VERSION 5.7 ;
BUSBITCHARS "[]" ;
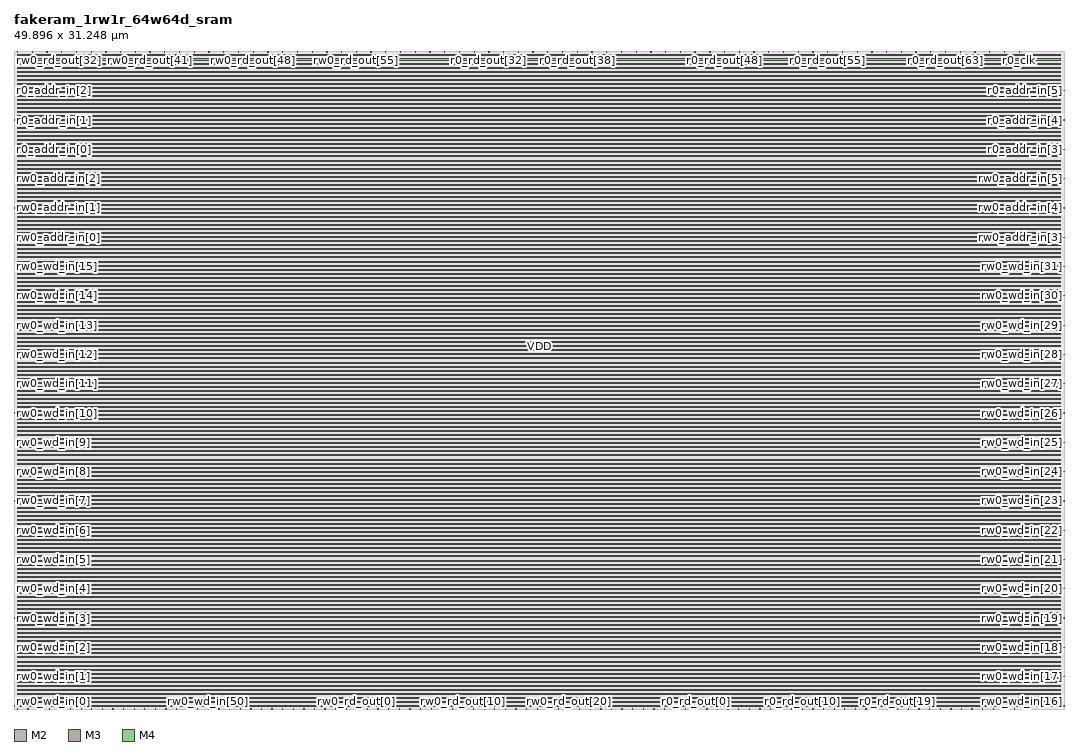
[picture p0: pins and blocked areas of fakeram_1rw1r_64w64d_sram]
MACRO fakeram_1rw1r_64w64d_sram
  FOREIGN fakeram_1rw1r_64w64d_sram 0 0 ;
  SYMMETRY X Y R90 ;
  SIZE 49.896 BY 31.248 ;
  CLASS BLOCK ;
  PIN rw0_wd_in[0]
    DIRECTION INPUT ;
    USE SIGNAL ;
    SHAPE ABUTMENT ;
    PORT
      LAYER M2 ;
      RECT 0.000 0.138 0.036 0.150 ;
    END
  END rw0_wd_in[0]
  PIN rw0_wd_in[1]
    DIRECTION INPUT ;
    USE SIGNAL ;
    SHAPE ABUTMENT ;
    PORT
      LAYER M2 ;
      RECT 0.000 1.530 0.036 1.542 ;
    END
  END rw0_wd_in[1]
  PIN rw0_wd_in[2]
    DIRECTION INPUT ;
    USE SIGNAL ;
    SHAPE ABUTMENT ;
    PORT
      LAYER M2 ;
      RECT 0.000 2.922 0.036 2.934 ;
    END
  END rw0_wd_in[2]
  PIN rw0_wd_in[3]
    DIRECTION INPUT ;
    USE SIGNAL ;
    SHAPE ABUTMENT ;
    PORT
      LAYER M2 ;
      RECT 0.000 4.314 0.036 4.326 ;
    END
  END rw0_wd_in[3]
  PIN rw0_wd_in[4]
    DIRECTION INPUT ;
    USE SIGNAL ;
    SHAPE ABUTMENT ;
    PORT
      LAYER M2 ;
      RECT 0.000 5.706 0.036 5.718 ;
    END
  END rw0_wd_in[4]
  PIN rw0_wd_in[5]
    DIRECTION INPUT ;
    USE SIGNAL ;
    SHAPE ABUTMENT ;
    PORT
      LAYER M2 ;
      RECT 0.000 7.098 0.036 7.110 ;
    END
  END rw0_wd_in[5]
  PIN rw0_wd_in[6]
    DIRECTION INPUT ;
    USE SIGNAL ;
    SHAPE ABUTMENT ;
    PORT
      LAYER M2 ;
      RECT 0.000 8.490 0.036 8.502 ;
    END
  END rw0_wd_in[6]
  PIN rw0_wd_in[7]
    DIRECTION INPUT ;
    USE SIGNAL ;
    SHAPE ABUTMENT ;
    PORT
      LAYER M2 ;
      RECT 0.000 9.882 0.036 9.894 ;
    END
  END rw0_wd_in[7]
  PIN rw0_wd_in[8]
    DIRECTION INPUT ;
    USE SIGNAL ;
    SHAPE ABUTMENT ;
    PORT
      LAYER M2 ;
      RECT 0.000 11.274 0.036 11.286 ;
    END
  END rw0_wd_in[8]
  PIN rw0_wd_in[9]
    DIRECTION INPUT ;
    USE SIGNAL ;
    SHAPE ABUTMENT ;
    PORT
      LAYER M2 ;
      RECT 0.000 12.666 0.036 12.678 ;
    END
  END rw0_wd_in[9]
  PIN rw0_wd_in[10]
    DIRECTION INPUT ;
    USE SIGNAL ;
    SHAPE ABUTMENT ;
    PORT
      LAYER M2 ;
      RECT 0.000 14.058 0.036 14.070 ;
    END
  END rw0_wd_in[10]
  PIN rw0_wd_in[11]
    DIRECTION INPUT ;
    USE SIGNAL ;
    SHAPE ABUTMENT ;
    PORT
      LAYER M2 ;
      RECT 0.000 15.450 0.036 15.462 ;
    END
  END rw0_wd_in[11]
  PIN rw0_wd_in[12]
    DIRECTION INPUT ;
    USE SIGNAL ;
    SHAPE ABUTMENT ;
    PORT
      LAYER M2 ;
      RECT 0.000 16.842 0.036 16.854 ;
    END
  END rw0_wd_in[12]
  PIN rw0_wd_in[13]
    DIRECTION INPUT ;
    USE SIGNAL ;
    SHAPE ABUTMENT ;
    PORT
      LAYER M2 ;
      RECT 0.000 18.234 0.036 18.246 ;
    END
  END rw0_wd_in[13]
  PIN rw0_wd_in[14]
    DIRECTION INPUT ;
    USE SIGNAL ;
    SHAPE ABUTMENT ;
    PORT
      LAYER M2 ;
      RECT 0.000 19.626 0.036 19.638 ;
    END
  END rw0_wd_in[14]
  PIN rw0_wd_in[15]
    DIRECTION INPUT ;
    USE SIGNAL ;
    SHAPE ABUTMENT ;
    PORT
      LAYER M2 ;
      RECT 0.000 21.018 0.036 21.030 ;
    END
  END rw0_wd_in[15]
  PIN rw0_wd_in[16]
    DIRECTION INPUT ;
    USE SIGNAL ;
    SHAPE ABUTMENT ;
    PORT
      LAYER M2 ;
      RECT 49.860 0.138 49.896 0.150 ;
    END
  END rw0_wd_in[16]
  PIN rw0_wd_in[17]
    DIRECTION INPUT ;
    USE SIGNAL ;
    SHAPE ABUTMENT ;
    PORT
      LAYER M2 ;
      RECT 49.860 1.530 49.896 1.542 ;
    END
  END rw0_wd_in[17]
  PIN rw0_wd_in[18]
    DIRECTION INPUT ;
    USE SIGNAL ;
    SHAPE ABUTMENT ;
    PORT
      LAYER M2 ;
      RECT 49.860 2.922 49.896 2.934 ;
    END
  END rw0_wd_in[18]
  PIN rw0_wd_in[19]
    DIRECTION INPUT ;
    USE SIGNAL ;
    SHAPE ABUTMENT ;
    PORT
      LAYER M2 ;
      RECT 49.860 4.314 49.896 4.326 ;
    END
  END rw0_wd_in[19]
  PIN rw0_wd_in[20]
    DIRECTION INPUT ;
    USE SIGNAL ;
    SHAPE ABUTMENT ;
    PORT
      LAYER M2 ;
      RECT 49.860 5.706 49.896 5.718 ;
    END
  END rw0_wd_in[20]
  PIN rw0_wd_in[21]
    DIRECTION INPUT ;
    USE SIGNAL ;
    SHAPE ABUTMENT ;
    PORT
      LAYER M2 ;
      RECT 49.860 7.098 49.896 7.110 ;
    END
  END rw0_wd_in[21]
  PIN rw0_wd_in[22]
    DIRECTION INPUT ;
    USE SIGNAL ;
    SHAPE ABUTMENT ;
    PORT
      LAYER M2 ;
      RECT 49.860 8.490 49.896 8.502 ;
    END
  END rw0_wd_in[22]
  PIN rw0_wd_in[23]
    DIRECTION INPUT ;
    USE SIGNAL ;
    SHAPE ABUTMENT ;
    PORT
      LAYER M2 ;
      RECT 49.860 9.882 49.896 9.894 ;
    END
  END rw0_wd_in[23]
  PIN rw0_wd_in[24]
    DIRECTION INPUT ;
    USE SIGNAL ;
    SHAPE ABUTMENT ;
    PORT
      LAYER M2 ;
      RECT 49.860 11.274 49.896 11.286 ;
    END
  END rw0_wd_in[24]
  PIN rw0_wd_in[25]
    DIRECTION INPUT ;
    USE SIGNAL ;
    SHAPE ABUTMENT ;
    PORT
      LAYER M2 ;
      RECT 49.860 12.666 49.896 12.678 ;
    END
  END rw0_wd_in[25]
  PIN rw0_wd_in[26]
    DIRECTION INPUT ;
    USE SIGNAL ;
    SHAPE ABUTMENT ;
    PORT
      LAYER M2 ;
      RECT 49.860 14.058 49.896 14.070 ;
    END
  END rw0_wd_in[26]
  PIN rw0_wd_in[27]
    DIRECTION INPUT ;
    USE SIGNAL ;
    SHAPE ABUTMENT ;
    PORT
      LAYER M2 ;
      RECT 49.860 15.450 49.896 15.462 ;
    END
  END rw0_wd_in[27]
  PIN rw0_wd_in[28]
    DIRECTION INPUT ;
    USE SIGNAL ;
    SHAPE ABUTMENT ;
    PORT
      LAYER M2 ;
      RECT 49.860 16.842 49.896 16.854 ;
    END
  END rw0_wd_in[28]
  PIN rw0_wd_in[29]
    DIRECTION INPUT ;
    USE SIGNAL ;
    SHAPE ABUTMENT ;
    PORT
      LAYER M2 ;
      RECT 49.860 18.234 49.896 18.246 ;
    END
  END rw0_wd_in[29]
  PIN rw0_wd_in[30]
    DIRECTION INPUT ;
    USE SIGNAL ;
    SHAPE ABUTMENT ;
    PORT
      LAYER M2 ;
      RECT 49.860 19.626 49.896 19.638 ;
    END
  END rw0_wd_in[30]
  PIN rw0_wd_in[31]
    DIRECTION INPUT ;
    USE SIGNAL ;
    SHAPE ABUTMENT ;
    PORT
      LAYER M2 ;
      RECT 49.860 21.018 49.896 21.030 ;
    END
  END rw0_wd_in[31]
  PIN rw0_wd_in[32]
    DIRECTION INPUT ;
    USE SIGNAL ;
    SHAPE ABUTMENT ;
    PORT
      LAYER M3 ;
      RECT 0.161 0.000 0.175 0.042 ;
    END
  END rw0_wd_in[32]
  PIN rw0_wd_in[33]
    DIRECTION INPUT ;
    USE SIGNAL ;
    SHAPE ABUTMENT ;
    PORT
      LAYER M3 ;
      RECT 0.665 0.000 0.679 0.042 ;
    END
  END rw0_wd_in[33]
  PIN rw0_wd_in[34]
    DIRECTION INPUT ;
    USE SIGNAL ;
    SHAPE ABUTMENT ;
    PORT
      LAYER M3 ;
      RECT 1.169 0.000 1.183 0.042 ;
    END
  END rw0_wd_in[34]
  PIN rw0_wd_in[35]
    DIRECTION INPUT ;
    USE SIGNAL ;
    SHAPE ABUTMENT ;
    PORT
      LAYER M3 ;
      RECT 1.673 0.000 1.687 0.042 ;
    END
  END rw0_wd_in[35]
  PIN rw0_wd_in[36]
    DIRECTION INPUT ;
    USE SIGNAL ;
    SHAPE ABUTMENT ;
    PORT
      LAYER M3 ;
      RECT 2.177 0.000 2.191 0.042 ;
    END
  END rw0_wd_in[36]
  PIN rw0_wd_in[37]
    DIRECTION INPUT ;
    USE SIGNAL ;
    SHAPE ABUTMENT ;
    PORT
      LAYER M3 ;
      RECT 2.681 0.000 2.695 0.042 ;
    END
  END rw0_wd_in[37]
  PIN rw0_wd_in[38]
    DIRECTION INPUT ;
    USE SIGNAL ;
    SHAPE ABUTMENT ;
    PORT
      LAYER M3 ;
      RECT 3.185 0.000 3.199 0.042 ;
    END
  END rw0_wd_in[38]
  PIN rw0_wd_in[39]
    DIRECTION INPUT ;
    USE SIGNAL ;
    SHAPE ABUTMENT ;
    PORT
      LAYER M3 ;
      RECT 3.689 0.000 3.703 0.042 ;
    END
  END rw0_wd_in[39]
  PIN rw0_wd_in[40]
    DIRECTION INPUT ;
    USE SIGNAL ;
    SHAPE ABUTMENT ;
    PORT
      LAYER M3 ;
      RECT 4.193 0.000 4.207 0.042 ;
    END
  END rw0_wd_in[40]
  PIN rw0_wd_in[41]
    DIRECTION INPUT ;
    USE SIGNAL ;
    SHAPE ABUTMENT ;
    PORT
      LAYER M3 ;
      RECT 4.697 0.000 4.711 0.042 ;
    END
  END rw0_wd_in[41]
  PIN rw0_wd_in[42]
    DIRECTION INPUT ;
    USE SIGNAL ;
    SHAPE ABUTMENT ;
    PORT
      LAYER M3 ;
      RECT 5.201 0.000 5.215 0.042 ;
    END
  END rw0_wd_in[42]
  PIN rw0_wd_in[43]
    DIRECTION INPUT ;
    USE SIGNAL ;
    SHAPE ABUTMENT ;
    PORT
      LAYER M3 ;
      RECT 5.705 0.000 5.719 0.042 ;
    END
  END rw0_wd_in[43]
  PIN rw0_wd_in[44]
    DIRECTION INPUT ;
    USE SIGNAL ;
    SHAPE ABUTMENT ;
    PORT
      LAYER M3 ;
      RECT 6.209 0.000 6.223 0.042 ;
    END
  END rw0_wd_in[44]
  PIN rw0_wd_in[45]
    DIRECTION INPUT ;
    USE SIGNAL ;
    SHAPE ABUTMENT ;
    PORT
      LAYER M3 ;
      RECT 6.713 0.000 6.727 0.042 ;
    END
  END rw0_wd_in[45]
  PIN rw0_wd_in[46]
    DIRECTION INPUT ;
    USE SIGNAL ;
    SHAPE ABUTMENT ;
    PORT
      LAYER M3 ;
      RECT 7.217 0.000 7.231 0.042 ;
    END
  END rw0_wd_in[46]
  PIN rw0_wd_in[47]
    DIRECTION INPUT ;
    USE SIGNAL ;
    SHAPE ABUTMENT ;
    PORT
      LAYER M3 ;
      RECT 7.721 0.000 7.735 0.042 ;
    END
  END rw0_wd_in[47]
  PIN rw0_wd_in[48]
    DIRECTION INPUT ;
    USE SIGNAL ;
    SHAPE ABUTMENT ;
    PORT
      LAYER M3 ;
      RECT 8.225 0.000 8.239 0.042 ;
    END
  END rw0_wd_in[48]
  PIN rw0_wd_in[49]
    DIRECTION INPUT ;
    USE SIGNAL ;
    SHAPE ABUTMENT ;
    PORT
      LAYER M3 ;
      RECT 8.729 0.000 8.743 0.042 ;
    END
  END rw0_wd_in[49]
  PIN rw0_wd_in[50]
    DIRECTION INPUT ;
    USE SIGNAL ;
    SHAPE ABUTMENT ;
    PORT
      LAYER M3 ;
      RECT 9.233 0.000 9.247 0.042 ;
    END
  END rw0_wd_in[50]
  PIN rw0_wd_in[51]
    DIRECTION INPUT ;
    USE SIGNAL ;
    SHAPE ABUTMENT ;
    PORT
      LAYER M3 ;
      RECT 9.737 0.000 9.751 0.042 ;
    END
  END rw0_wd_in[51]
  PIN rw0_wd_in[52]
    DIRECTION INPUT ;
    USE SIGNAL ;
    SHAPE ABUTMENT ;
    PORT
      LAYER M3 ;
      RECT 10.241 0.000 10.255 0.042 ;
    END
  END rw0_wd_in[52]
  PIN rw0_wd_in[53]
    DIRECTION INPUT ;
    USE SIGNAL ;
    SHAPE ABUTMENT ;
    PORT
      LAYER M3 ;
      RECT 10.745 0.000 10.759 0.042 ;
    END
  END rw0_wd_in[53]
  PIN rw0_wd_in[54]
    DIRECTION INPUT ;
    USE SIGNAL ;
    SHAPE ABUTMENT ;
    PORT
      LAYER M3 ;
      RECT 11.249 0.000 11.263 0.042 ;
    END
  END rw0_wd_in[54]
  PIN rw0_wd_in[55]
    DIRECTION INPUT ;
    USE SIGNAL ;
    SHAPE ABUTMENT ;
    PORT
      LAYER M3 ;
      RECT 11.753 0.000 11.767 0.042 ;
    END
  END rw0_wd_in[55]
  PIN rw0_wd_in[56]
    DIRECTION INPUT ;
    USE SIGNAL ;
    SHAPE ABUTMENT ;
    PORT
      LAYER M3 ;
      RECT 12.257 0.000 12.271 0.042 ;
    END
  END rw0_wd_in[56]
  PIN rw0_wd_in[57]
    DIRECTION INPUT ;
    USE SIGNAL ;
    SHAPE ABUTMENT ;
    PORT
      LAYER M3 ;
      RECT 12.761 0.000 12.775 0.042 ;
    END
  END rw0_wd_in[57]
  PIN rw0_wd_in[58]
    DIRECTION INPUT ;
    USE SIGNAL ;
    SHAPE ABUTMENT ;
    PORT
      LAYER M3 ;
      RECT 13.265 0.000 13.279 0.042 ;
    END
  END rw0_wd_in[58]
  PIN rw0_wd_in[59]
    DIRECTION INPUT ;
    USE SIGNAL ;
    SHAPE ABUTMENT ;
    PORT
      LAYER M3 ;
      RECT 13.769 0.000 13.783 0.042 ;
    END
  END rw0_wd_in[59]
  PIN rw0_wd_in[60]
    DIRECTION INPUT ;
    USE SIGNAL ;
    SHAPE ABUTMENT ;
    PORT
      LAYER M3 ;
      RECT 14.273 0.000 14.287 0.042 ;
    END
  END rw0_wd_in[60]
  PIN rw0_wd_in[61]
    DIRECTION INPUT ;
    USE SIGNAL ;
    SHAPE ABUTMENT ;
    PORT
      LAYER M3 ;
      RECT 14.777 0.000 14.791 0.042 ;
    END
  END rw0_wd_in[61]
  PIN rw0_wd_in[62]
    DIRECTION INPUT ;
    USE SIGNAL ;
    SHAPE ABUTMENT ;
    PORT
      LAYER M3 ;
      RECT 15.281 0.000 15.295 0.042 ;
    END
  END rw0_wd_in[62]
  PIN rw0_wd_in[63]
    DIRECTION INPUT ;
    USE SIGNAL ;
    SHAPE ABUTMENT ;
    PORT
      LAYER M3 ;
      RECT 15.785 0.000 15.799 0.042 ;
    END
  END rw0_wd_in[63]
  PIN rw0_rd_out[0]
    DIRECTION OUTPUT ;
    USE SIGNAL ;
    SHAPE ABUTMENT ;
    PORT
      LAYER M3 ;
      RECT 16.289 0.000 16.303 0.042 ;
    END
  END rw0_rd_out[0]
  PIN rw0_rd_out[1]
    DIRECTION OUTPUT ;
    USE SIGNAL ;
    SHAPE ABUTMENT ;
    PORT
      LAYER M3 ;
      RECT 16.793 0.000 16.807 0.042 ;
    END
  END rw0_rd_out[1]
  PIN rw0_rd_out[2]
    DIRECTION OUTPUT ;
    USE SIGNAL ;
    SHAPE ABUTMENT ;
    PORT
      LAYER M3 ;
      RECT 17.297 0.000 17.311 0.042 ;
    END
  END rw0_rd_out[2]
  PIN rw0_rd_out[3]
    DIRECTION OUTPUT ;
    USE SIGNAL ;
    SHAPE ABUTMENT ;
    PORT
      LAYER M3 ;
      RECT 17.801 0.000 17.815 0.042 ;
    END
  END rw0_rd_out[3]
  PIN rw0_rd_out[4]
    DIRECTION OUTPUT ;
    USE SIGNAL ;
    SHAPE ABUTMENT ;
    PORT
      LAYER M3 ;
      RECT 18.305 0.000 18.319 0.042 ;
    END
  END rw0_rd_out[4]
  PIN rw0_rd_out[5]
    DIRECTION OUTPUT ;
    USE SIGNAL ;
    SHAPE ABUTMENT ;
    PORT
      LAYER M3 ;
      RECT 18.809 0.000 18.823 0.042 ;
    END
  END rw0_rd_out[5]
  PIN rw0_rd_out[6]
    DIRECTION OUTPUT ;
    USE SIGNAL ;
    SHAPE ABUTMENT ;
    PORT
      LAYER M3 ;
      RECT 19.313 0.000 19.327 0.042 ;
    END
  END rw0_rd_out[6]
  PIN rw0_rd_out[7]
    DIRECTION OUTPUT ;
    USE SIGNAL ;
    SHAPE ABUTMENT ;
    PORT
      LAYER M3 ;
      RECT 19.817 0.000 19.831 0.042 ;
    END
  END rw0_rd_out[7]
  PIN rw0_rd_out[8]
    DIRECTION OUTPUT ;
    USE SIGNAL ;
    SHAPE ABUTMENT ;
    PORT
      LAYER M3 ;
      RECT 20.321 0.000 20.335 0.042 ;
    END
  END rw0_rd_out[8]
  PIN rw0_rd_out[9]
    DIRECTION OUTPUT ;
    USE SIGNAL ;
    SHAPE ABUTMENT ;
    PORT
      LAYER M3 ;
      RECT 20.825 0.000 20.839 0.042 ;
    END
  END rw0_rd_out[9]
  PIN rw0_rd_out[10]
    DIRECTION OUTPUT ;
    USE SIGNAL ;
    SHAPE ABUTMENT ;
    PORT
      LAYER M3 ;
      RECT 21.329 0.000 21.343 0.042 ;
    END
  END rw0_rd_out[10]
  PIN rw0_rd_out[11]
    DIRECTION OUTPUT ;
    USE SIGNAL ;
    SHAPE ABUTMENT ;
    PORT
      LAYER M3 ;
      RECT 21.833 0.000 21.847 0.042 ;
    END
  END rw0_rd_out[11]
  PIN rw0_rd_out[12]
    DIRECTION OUTPUT ;
    USE SIGNAL ;
    SHAPE ABUTMENT ;
    PORT
      LAYER M3 ;
      RECT 22.337 0.000 22.351 0.042 ;
    END
  END rw0_rd_out[12]
  PIN rw0_rd_out[13]
    DIRECTION OUTPUT ;
    USE SIGNAL ;
    SHAPE ABUTMENT ;
    PORT
      LAYER M3 ;
      RECT 22.841 0.000 22.855 0.042 ;
    END
  END rw0_rd_out[13]
  PIN rw0_rd_out[14]
    DIRECTION OUTPUT ;
    USE SIGNAL ;
    SHAPE ABUTMENT ;
    PORT
      LAYER M3 ;
      RECT 23.345 0.000 23.359 0.042 ;
    END
  END rw0_rd_out[14]
  PIN rw0_rd_out[15]
    DIRECTION OUTPUT ;
    USE SIGNAL ;
    SHAPE ABUTMENT ;
    PORT
      LAYER M3 ;
      RECT 23.849 0.000 23.863 0.042 ;
    END
  END rw0_rd_out[15]
  PIN rw0_rd_out[16]
    DIRECTION OUTPUT ;
    USE SIGNAL ;
    SHAPE ABUTMENT ;
    PORT
      LAYER M3 ;
      RECT 24.353 0.000 24.367 0.042 ;
    END
  END rw0_rd_out[16]
  PIN rw0_rd_out[17]
    DIRECTION OUTPUT ;
    USE SIGNAL ;
    SHAPE ABUTMENT ;
    PORT
      LAYER M3 ;
      RECT 24.857 0.000 24.871 0.042 ;
    END
  END rw0_rd_out[17]
  PIN rw0_rd_out[18]
    DIRECTION OUTPUT ;
    USE SIGNAL ;
    SHAPE ABUTMENT ;
    PORT
      LAYER M3 ;
      RECT 25.361 0.000 25.375 0.042 ;
    END
  END rw0_rd_out[18]
  PIN rw0_rd_out[19]
    DIRECTION OUTPUT ;
    USE SIGNAL ;
    SHAPE ABUTMENT ;
    PORT
      LAYER M3 ;
      RECT 25.865 0.000 25.879 0.042 ;
    END
  END rw0_rd_out[19]
  PIN rw0_rd_out[20]
    DIRECTION OUTPUT ;
    USE SIGNAL ;
    SHAPE ABUTMENT ;
    PORT
      LAYER M3 ;
      RECT 26.369 0.000 26.383 0.042 ;
    END
  END rw0_rd_out[20]
  PIN rw0_rd_out[21]
    DIRECTION OUTPUT ;
    USE SIGNAL ;
    SHAPE ABUTMENT ;
    PORT
      LAYER M3 ;
      RECT 26.873 0.000 26.887 0.042 ;
    END
  END rw0_rd_out[21]
  PIN rw0_rd_out[22]
    DIRECTION OUTPUT ;
    USE SIGNAL ;
    SHAPE ABUTMENT ;
    PORT
      LAYER M3 ;
      RECT 27.377 0.000 27.391 0.042 ;
    END
  END rw0_rd_out[22]
  PIN rw0_rd_out[23]
    DIRECTION OUTPUT ;
    USE SIGNAL ;
    SHAPE ABUTMENT ;
    PORT
      LAYER M3 ;
      RECT 27.881 0.000 27.895 0.042 ;
    END
  END rw0_rd_out[23]
  PIN rw0_rd_out[24]
    DIRECTION OUTPUT ;
    USE SIGNAL ;
    SHAPE ABUTMENT ;
    PORT
      LAYER M3 ;
      RECT 28.385 0.000 28.399 0.042 ;
    END
  END rw0_rd_out[24]
  PIN rw0_rd_out[25]
    DIRECTION OUTPUT ;
    USE SIGNAL ;
    SHAPE ABUTMENT ;
    PORT
      LAYER M3 ;
      RECT 28.889 0.000 28.903 0.042 ;
    END
  END rw0_rd_out[25]
  PIN rw0_rd_out[26]
    DIRECTION OUTPUT ;
    USE SIGNAL ;
    SHAPE ABUTMENT ;
    PORT
      LAYER M3 ;
      RECT 29.393 0.000 29.407 0.042 ;
    END
  END rw0_rd_out[26]
  PIN rw0_rd_out[27]
    DIRECTION OUTPUT ;
    USE SIGNAL ;
    SHAPE ABUTMENT ;
    PORT
      LAYER M3 ;
      RECT 29.897 0.000 29.911 0.042 ;
    END
  END rw0_rd_out[27]
  PIN rw0_rd_out[28]
    DIRECTION OUTPUT ;
    USE SIGNAL ;
    SHAPE ABUTMENT ;
    PORT
      LAYER M3 ;
      RECT 30.401 0.000 30.415 0.042 ;
    END
  END rw0_rd_out[28]
  PIN rw0_rd_out[29]
    DIRECTION OUTPUT ;
    USE SIGNAL ;
    SHAPE ABUTMENT ;
    PORT
      LAYER M3 ;
      RECT 30.905 0.000 30.919 0.042 ;
    END
  END rw0_rd_out[29]
  PIN rw0_rd_out[30]
    DIRECTION OUTPUT ;
    USE SIGNAL ;
    SHAPE ABUTMENT ;
    PORT
      LAYER M3 ;
      RECT 31.409 0.000 31.423 0.042 ;
    END
  END rw0_rd_out[30]
  PIN rw0_rd_out[31]
    DIRECTION OUTPUT ;
    USE SIGNAL ;
    SHAPE ABUTMENT ;
    PORT
      LAYER M3 ;
      RECT 31.913 0.000 31.927 0.042 ;
    END
  END rw0_rd_out[31]
  PIN rw0_rd_out[32]
    DIRECTION OUTPUT ;
    USE SIGNAL ;
    SHAPE ABUTMENT ;
    PORT
      LAYER M3 ;
      RECT 0.161 31.206 0.175 31.248 ;
    END
  END rw0_rd_out[32]
  PIN rw0_rd_out[33]
    DIRECTION OUTPUT ;
    USE SIGNAL ;
    SHAPE ABUTMENT ;
    PORT
      LAYER M3 ;
      RECT 0.861 31.206 0.875 31.248 ;
    END
  END rw0_rd_out[33]
  PIN rw0_rd_out[34]
    DIRECTION OUTPUT ;
    USE SIGNAL ;
    SHAPE ABUTMENT ;
    PORT
      LAYER M3 ;
      RECT 1.561 31.206 1.575 31.248 ;
    END
  END rw0_rd_out[34]
  PIN rw0_rd_out[35]
    DIRECTION OUTPUT ;
    USE SIGNAL ;
    SHAPE ABUTMENT ;
    PORT
      LAYER M3 ;
      RECT 2.261 31.206 2.275 31.248 ;
    END
  END rw0_rd_out[35]
  PIN rw0_rd_out[36]
    DIRECTION OUTPUT ;
    USE SIGNAL ;
    SHAPE ABUTMENT ;
    PORT
      LAYER M3 ;
      RECT 2.961 31.206 2.975 31.248 ;
    END
  END rw0_rd_out[36]
  PIN rw0_rd_out[37]
    DIRECTION OUTPUT ;
    USE SIGNAL ;
    SHAPE ABUTMENT ;
    PORT
      LAYER M3 ;
      RECT 3.661 31.206 3.675 31.248 ;
    END
  END rw0_rd_out[37]
  PIN rw0_rd_out[38]
    DIRECTION OUTPUT ;
    USE SIGNAL ;
    SHAPE ABUTMENT ;
    PORT
      LAYER M3 ;
      RECT 4.361 31.206 4.375 31.248 ;
    END
  END rw0_rd_out[38]
  PIN rw0_rd_out[39]
    DIRECTION OUTPUT ;
    USE SIGNAL ;
    SHAPE ABUTMENT ;
    PORT
      LAYER M3 ;
      RECT 5.061 31.206 5.075 31.248 ;
    END
  END rw0_rd_out[39]
  PIN rw0_rd_out[40]
    DIRECTION OUTPUT ;
    USE SIGNAL ;
    SHAPE ABUTMENT ;
    PORT
      LAYER M3 ;
      RECT 5.761 31.206 5.775 31.248 ;
    END
  END rw0_rd_out[40]
  PIN rw0_rd_out[41]
    DIRECTION OUTPUT ;
    USE SIGNAL ;
    SHAPE ABUTMENT ;
    PORT
      LAYER M3 ;
      RECT 6.461 31.206 6.475 31.248 ;
    END
  END rw0_rd_out[41]
  PIN rw0_rd_out[42]
    DIRECTION OUTPUT ;
    USE SIGNAL ;
    SHAPE ABUTMENT ;
    PORT
      LAYER M3 ;
      RECT 7.161 31.206 7.175 31.248 ;
    END
  END rw0_rd_out[42]
  PIN rw0_rd_out[43]
    DIRECTION OUTPUT ;
    USE SIGNAL ;
    SHAPE ABUTMENT ;
    PORT
      LAYER M3 ;
      RECT 7.861 31.206 7.875 31.248 ;
    END
  END rw0_rd_out[43]
  PIN rw0_rd_out[44]
    DIRECTION OUTPUT ;
    USE SIGNAL ;
    SHAPE ABUTMENT ;
    PORT
      LAYER M3 ;
      RECT 8.561 31.206 8.575 31.248 ;
    END
  END rw0_rd_out[44]
  PIN rw0_rd_out[45]
    DIRECTION OUTPUT ;
    USE SIGNAL ;
    SHAPE ABUTMENT ;
    PORT
      LAYER M3 ;
      RECT 9.261 31.206 9.275 31.248 ;
    END
  END rw0_rd_out[45]
  PIN rw0_rd_out[46]
    DIRECTION OUTPUT ;
    USE SIGNAL ;
    SHAPE ABUTMENT ;
    PORT
      LAYER M3 ;
      RECT 9.961 31.206 9.975 31.248 ;
    END
  END rw0_rd_out[46]
  PIN rw0_rd_out[47]
    DIRECTION OUTPUT ;
    USE SIGNAL ;
    SHAPE ABUTMENT ;
    PORT
      LAYER M3 ;
      RECT 10.661 31.206 10.675 31.248 ;
    END
  END rw0_rd_out[47]
  PIN rw0_rd_out[48]
    DIRECTION OUTPUT ;
    USE SIGNAL ;
    SHAPE ABUTMENT ;
    PORT
      LAYER M3 ;
      RECT 11.361 31.206 11.375 31.248 ;
    END
  END rw0_rd_out[48]
  PIN rw0_rd_out[49]
    DIRECTION OUTPUT ;
    USE SIGNAL ;
    SHAPE ABUTMENT ;
    PORT
      LAYER M3 ;
      RECT 12.061 31.206 12.075 31.248 ;
    END
  END rw0_rd_out[49]
  PIN rw0_rd_out[50]
    DIRECTION OUTPUT ;
    USE SIGNAL ;
    SHAPE ABUTMENT ;
    PORT
      LAYER M3 ;
      RECT 12.761 31.206 12.775 31.248 ;
    END
  END rw0_rd_out[50]
  PIN rw0_rd_out[51]
    DIRECTION OUTPUT ;
    USE SIGNAL ;
    SHAPE ABUTMENT ;
    PORT
      LAYER M3 ;
      RECT 13.461 31.206 13.475 31.248 ;
    END
  END rw0_rd_out[51]
  PIN rw0_rd_out[52]
    DIRECTION OUTPUT ;
    USE SIGNAL ;
    SHAPE ABUTMENT ;
    PORT
      LAYER M3 ;
      RECT 14.161 31.206 14.175 31.248 ;
    END
  END rw0_rd_out[52]
  PIN rw0_rd_out[53]
    DIRECTION OUTPUT ;
    USE SIGNAL ;
    SHAPE ABUTMENT ;
    PORT
      LAYER M3 ;
      RECT 14.861 31.206 14.875 31.248 ;
    END
  END rw0_rd_out[53]
  PIN rw0_rd_out[54]
    DIRECTION OUTPUT ;
    USE SIGNAL ;
    SHAPE ABUTMENT ;
    PORT
      LAYER M3 ;
      RECT 15.561 31.206 15.575 31.248 ;
    END
  END rw0_rd_out[54]
  PIN rw0_rd_out[55]
    DIRECTION OUTPUT ;
    USE SIGNAL ;
    SHAPE ABUTMENT ;
    PORT
      LAYER M3 ;
      RECT 16.261 31.206 16.275 31.248 ;
    END
  END rw0_rd_out[55]
  PIN rw0_rd_out[56]
    DIRECTION OUTPUT ;
    USE SIGNAL ;
    SHAPE ABUTMENT ;
    PORT
      LAYER M3 ;
      RECT 16.961 31.206 16.975 31.248 ;
    END
  END rw0_rd_out[56]
  PIN rw0_rd_out[57]
    DIRECTION OUTPUT ;
    USE SIGNAL ;
    SHAPE ABUTMENT ;
    PORT
      LAYER M3 ;
      RECT 17.661 31.206 17.675 31.248 ;
    END
  END rw0_rd_out[57]
  PIN rw0_rd_out[58]
    DIRECTION OUTPUT ;
    USE SIGNAL ;
    SHAPE ABUTMENT ;
    PORT
      LAYER M3 ;
      RECT 18.361 31.206 18.375 31.248 ;
    END
  END rw0_rd_out[58]
  PIN rw0_rd_out[59]
    DIRECTION OUTPUT ;
    USE SIGNAL ;
    SHAPE ABUTMENT ;
    PORT
      LAYER M3 ;
      RECT 19.061 31.206 19.075 31.248 ;
    END
  END rw0_rd_out[59]
  PIN rw0_rd_out[60]
    DIRECTION OUTPUT ;
    USE SIGNAL ;
    SHAPE ABUTMENT ;
    PORT
      LAYER M3 ;
      RECT 19.761 31.206 19.775 31.248 ;
    END
  END rw0_rd_out[60]
  PIN rw0_rd_out[61]
    DIRECTION OUTPUT ;
    USE SIGNAL ;
    SHAPE ABUTMENT ;
    PORT
      LAYER M3 ;
      RECT 20.461 31.206 20.475 31.248 ;
    END
  END rw0_rd_out[61]
  PIN rw0_rd_out[62]
    DIRECTION OUTPUT ;
    USE SIGNAL ;
    SHAPE ABUTMENT ;
    PORT
      LAYER M3 ;
      RECT 21.161 31.206 21.175 31.248 ;
    END
  END rw0_rd_out[62]
  PIN rw0_rd_out[63]
    DIRECTION OUTPUT ;
    USE SIGNAL ;
    SHAPE ABUTMENT ;
    PORT
      LAYER M3 ;
      RECT 21.861 31.206 21.875 31.248 ;
    END
  END rw0_rd_out[63]
  PIN r0_rd_out[0]
    DIRECTION OUTPUT ;
    USE SIGNAL ;
    SHAPE ABUTMENT ;
    PORT
      LAYER M3 ;
      RECT 32.417 0.000 32.431 0.042 ;
    END
  END r0_rd_out[0]
  PIN r0_rd_out[1]
    DIRECTION OUTPUT ;
    USE SIGNAL ;
    SHAPE ABUTMENT ;
    PORT
      LAYER M3 ;
      RECT 32.921 0.000 32.935 0.042 ;
    END
  END r0_rd_out[1]
  PIN r0_rd_out[2]
    DIRECTION OUTPUT ;
    USE SIGNAL ;
    SHAPE ABUTMENT ;
    PORT
      LAYER M3 ;
      RECT 33.425 0.000 33.439 0.042 ;
    END
  END r0_rd_out[2]
  PIN r0_rd_out[3]
    DIRECTION OUTPUT ;
    USE SIGNAL ;
    SHAPE ABUTMENT ;
    PORT
      LAYER M3 ;
      RECT 33.929 0.000 33.943 0.042 ;
    END
  END r0_rd_out[3]
  PIN r0_rd_out[4]
    DIRECTION OUTPUT ;
    USE SIGNAL ;
    SHAPE ABUTMENT ;
    PORT
      LAYER M3 ;
      RECT 34.433 0.000 34.447 0.042 ;
    END
  END r0_rd_out[4]
  PIN r0_rd_out[5]
    DIRECTION OUTPUT ;
    USE SIGNAL ;
    SHAPE ABUTMENT ;
    PORT
      LAYER M3 ;
      RECT 34.937 0.000 34.951 0.042 ;
    END
  END r0_rd_out[5]
  PIN r0_rd_out[6]
    DIRECTION OUTPUT ;
    USE SIGNAL ;
    SHAPE ABUTMENT ;
    PORT
      LAYER M3 ;
      RECT 35.441 0.000 35.455 0.042 ;
    END
  END r0_rd_out[6]
  PIN r0_rd_out[7]
    DIRECTION OUTPUT ;
    USE SIGNAL ;
    SHAPE ABUTMENT ;
    PORT
      LAYER M3 ;
      RECT 35.945 0.000 35.959 0.042 ;
    END
  END r0_rd_out[7]
  PIN r0_rd_out[8]
    DIRECTION OUTPUT ;
    USE SIGNAL ;
    SHAPE ABUTMENT ;
    PORT
      LAYER M3 ;
      RECT 36.449 0.000 36.463 0.042 ;
    END
  END r0_rd_out[8]
  PIN r0_rd_out[9]
    DIRECTION OUTPUT ;
    USE SIGNAL ;
    SHAPE ABUTMENT ;
    PORT
      LAYER M3 ;
      RECT 36.953 0.000 36.967 0.042 ;
    END
  END r0_rd_out[9]
  PIN r0_rd_out[10]
    DIRECTION OUTPUT ;
    USE SIGNAL ;
    SHAPE ABUTMENT ;
    PORT
      LAYER M3 ;
      RECT 37.457 0.000 37.471 0.042 ;
    END
  END r0_rd_out[10]
  PIN r0_rd_out[11]
    DIRECTION OUTPUT ;
    USE SIGNAL ;
    SHAPE ABUTMENT ;
    PORT
      LAYER M3 ;
      RECT 37.961 0.000 37.975 0.042 ;
    END
  END r0_rd_out[11]
  PIN r0_rd_out[12]
    DIRECTION OUTPUT ;
    USE SIGNAL ;
    SHAPE ABUTMENT ;
    PORT
      LAYER M3 ;
      RECT 38.465 0.000 38.479 0.042 ;
    END
  END r0_rd_out[12]
  PIN r0_rd_out[13]
    DIRECTION OUTPUT ;
    USE SIGNAL ;
    SHAPE ABUTMENT ;
    PORT
      LAYER M3 ;
      RECT 38.969 0.000 38.983 0.042 ;
    END
  END r0_rd_out[13]
  PIN r0_rd_out[14]
    DIRECTION OUTPUT ;
    USE SIGNAL ;
    SHAPE ABUTMENT ;
    PORT
      LAYER M3 ;
      RECT 39.473 0.000 39.487 0.042 ;
    END
  END r0_rd_out[14]
  PIN r0_rd_out[15]
    DIRECTION OUTPUT ;
    USE SIGNAL ;
    SHAPE ABUTMENT ;
    PORT
      LAYER M3 ;
      RECT 39.977 0.000 39.991 0.042 ;
    END
  END r0_rd_out[15]
  PIN r0_rd_out[16]
    DIRECTION OUTPUT ;
    USE SIGNAL ;
    SHAPE ABUTMENT ;
    PORT
      LAYER M3 ;
      RECT 40.481 0.000 40.495 0.042 ;
    END
  END r0_rd_out[16]
  PIN r0_rd_out[17]
    DIRECTION OUTPUT ;
    USE SIGNAL ;
    SHAPE ABUTMENT ;
    PORT
      LAYER M3 ;
      RECT 40.985 0.000 40.999 0.042 ;
    END
  END r0_rd_out[17]
  PIN r0_rd_out[18]
    DIRECTION OUTPUT ;
    USE SIGNAL ;
    SHAPE ABUTMENT ;
    PORT
      LAYER M3 ;
      RECT 41.489 0.000 41.503 0.042 ;
    END
  END r0_rd_out[18]
  PIN r0_rd_out[19]
    DIRECTION OUTPUT ;
    USE SIGNAL ;
    SHAPE ABUTMENT ;
    PORT
      LAYER M3 ;
      RECT 41.993 0.000 42.007 0.042 ;
    END
  END r0_rd_out[19]
  PIN r0_rd_out[20]
    DIRECTION OUTPUT ;
    USE SIGNAL ;
    SHAPE ABUTMENT ;
    PORT
      LAYER M3 ;
      RECT 42.497 0.000 42.511 0.042 ;
    END
  END r0_rd_out[20]
  PIN r0_rd_out[21]
    DIRECTION OUTPUT ;
    USE SIGNAL ;
    SHAPE ABUTMENT ;
    PORT
      LAYER M3 ;
      RECT 43.001 0.000 43.015 0.042 ;
    END
  END r0_rd_out[21]
  PIN r0_rd_out[22]
    DIRECTION OUTPUT ;
    USE SIGNAL ;
    SHAPE ABUTMENT ;
    PORT
      LAYER M3 ;
      RECT 43.505 0.000 43.519 0.042 ;
    END
  END r0_rd_out[22]
  PIN r0_rd_out[23]
    DIRECTION OUTPUT ;
    USE SIGNAL ;
    SHAPE ABUTMENT ;
    PORT
      LAYER M3 ;
      RECT 44.009 0.000 44.023 0.042 ;
    END
  END r0_rd_out[23]
  PIN r0_rd_out[24]
    DIRECTION OUTPUT ;
    USE SIGNAL ;
    SHAPE ABUTMENT ;
    PORT
      LAYER M3 ;
      RECT 44.513 0.000 44.527 0.042 ;
    END
  END r0_rd_out[24]
  PIN r0_rd_out[25]
    DIRECTION OUTPUT ;
    USE SIGNAL ;
    SHAPE ABUTMENT ;
    PORT
      LAYER M3 ;
      RECT 45.017 0.000 45.031 0.042 ;
    END
  END r0_rd_out[25]
  PIN r0_rd_out[26]
    DIRECTION OUTPUT ;
    USE SIGNAL ;
    SHAPE ABUTMENT ;
    PORT
      LAYER M3 ;
      RECT 45.521 0.000 45.535 0.042 ;
    END
  END r0_rd_out[26]
  PIN r0_rd_out[27]
    DIRECTION OUTPUT ;
    USE SIGNAL ;
    SHAPE ABUTMENT ;
    PORT
      LAYER M3 ;
      RECT 46.025 0.000 46.039 0.042 ;
    END
  END r0_rd_out[27]
  PIN r0_rd_out[28]
    DIRECTION OUTPUT ;
    USE SIGNAL ;
    SHAPE ABUTMENT ;
    PORT
      LAYER M3 ;
      RECT 46.529 0.000 46.543 0.042 ;
    END
  END r0_rd_out[28]
  PIN r0_rd_out[29]
    DIRECTION OUTPUT ;
    USE SIGNAL ;
    SHAPE ABUTMENT ;
    PORT
      LAYER M3 ;
      RECT 47.033 0.000 47.047 0.042 ;
    END
  END r0_rd_out[29]
  PIN r0_rd_out[30]
    DIRECTION OUTPUT ;
    USE SIGNAL ;
    SHAPE ABUTMENT ;
    PORT
      LAYER M3 ;
      RECT 47.537 0.000 47.551 0.042 ;
    END
  END r0_rd_out[30]
  PIN r0_rd_out[31]
    DIRECTION OUTPUT ;
    USE SIGNAL ;
    SHAPE ABUTMENT ;
    PORT
      LAYER M3 ;
      RECT 48.041 0.000 48.055 0.042 ;
    END
  END r0_rd_out[31]
  PIN r0_rd_out[32]
    DIRECTION OUTPUT ;
    USE SIGNAL ;
    SHAPE ABUTMENT ;
    PORT
      LAYER M3 ;
      RECT 22.561 31.206 22.575 31.248 ;
    END
  END r0_rd_out[32]
  PIN r0_rd_out[33]
    DIRECTION OUTPUT ;
    USE SIGNAL ;
    SHAPE ABUTMENT ;
    PORT
      LAYER M3 ;
      RECT 23.261 31.206 23.275 31.248 ;
    END
  END r0_rd_out[33]
  PIN r0_rd_out[34]
    DIRECTION OUTPUT ;
    USE SIGNAL ;
    SHAPE ABUTMENT ;
    PORT
      LAYER M3 ;
      RECT 23.961 31.206 23.975 31.248 ;
    END
  END r0_rd_out[34]
  PIN r0_rd_out[35]
    DIRECTION OUTPUT ;
    USE SIGNAL ;
    SHAPE ABUTMENT ;
    PORT
      LAYER M3 ;
      RECT 24.661 31.206 24.675 31.248 ;
    END
  END r0_rd_out[35]
  PIN r0_rd_out[36]
    DIRECTION OUTPUT ;
    USE SIGNAL ;
    SHAPE ABUTMENT ;
    PORT
      LAYER M3 ;
      RECT 25.361 31.206 25.375 31.248 ;
    END
  END r0_rd_out[36]
  PIN r0_rd_out[37]
    DIRECTION OUTPUT ;
    USE SIGNAL ;
    SHAPE ABUTMENT ;
    PORT
      LAYER M3 ;
      RECT 26.061 31.206 26.075 31.248 ;
    END
  END r0_rd_out[37]
  PIN r0_rd_out[38]
    DIRECTION OUTPUT ;
    USE SIGNAL ;
    SHAPE ABUTMENT ;
    PORT
      LAYER M3 ;
      RECT 26.761 31.206 26.775 31.248 ;
    END
  END r0_rd_out[38]
  PIN r0_rd_out[39]
    DIRECTION OUTPUT ;
    USE SIGNAL ;
    SHAPE ABUTMENT ;
    PORT
      LAYER M3 ;
      RECT 27.461 31.206 27.475 31.248 ;
    END
  END r0_rd_out[39]
  PIN r0_rd_out[40]
    DIRECTION OUTPUT ;
    USE SIGNAL ;
    SHAPE ABUTMENT ;
    PORT
      LAYER M3 ;
      RECT 28.161 31.206 28.175 31.248 ;
    END
  END r0_rd_out[40]
  PIN r0_rd_out[41]
    DIRECTION OUTPUT ;
    USE SIGNAL ;
    SHAPE ABUTMENT ;
    PORT
      LAYER M3 ;
      RECT 28.861 31.206 28.875 31.248 ;
    END
  END r0_rd_out[41]
  PIN r0_rd_out[42]
    DIRECTION OUTPUT ;
    USE SIGNAL ;
    SHAPE ABUTMENT ;
    PORT
      LAYER M3 ;
      RECT 29.561 31.206 29.575 31.248 ;
    END
  END r0_rd_out[42]
  PIN r0_rd_out[43]
    DIRECTION OUTPUT ;
    USE SIGNAL ;
    SHAPE ABUTMENT ;
    PORT
      LAYER M3 ;
      RECT 30.261 31.206 30.275 31.248 ;
    END
  END r0_rd_out[43]
  PIN r0_rd_out[44]
    DIRECTION OUTPUT ;
    USE SIGNAL ;
    SHAPE ABUTMENT ;
    PORT
      LAYER M3 ;
      RECT 30.961 31.206 30.975 31.248 ;
    END
  END r0_rd_out[44]
  PIN r0_rd_out[45]
    DIRECTION OUTPUT ;
    USE SIGNAL ;
    SHAPE ABUTMENT ;
    PORT
      LAYER M3 ;
      RECT 31.661 31.206 31.675 31.248 ;
    END
  END r0_rd_out[45]
  PIN r0_rd_out[46]
    DIRECTION OUTPUT ;
    USE SIGNAL ;
    SHAPE ABUTMENT ;
    PORT
      LAYER M3 ;
      RECT 32.361 31.206 32.375 31.248 ;
    END
  END r0_rd_out[46]
  PIN r0_rd_out[47]
    DIRECTION OUTPUT ;
    USE SIGNAL ;
    SHAPE ABUTMENT ;
    PORT
      LAYER M3 ;
      RECT 33.061 31.206 33.075 31.248 ;
    END
  END r0_rd_out[47]
  PIN r0_rd_out[48]
    DIRECTION OUTPUT ;
    USE SIGNAL ;
    SHAPE ABUTMENT ;
    PORT
      LAYER M3 ;
      RECT 33.761 31.206 33.775 31.248 ;
    END
  END r0_rd_out[48]
  PIN r0_rd_out[49]
    DIRECTION OUTPUT ;
    USE SIGNAL ;
    SHAPE ABUTMENT ;
    PORT
      LAYER M3 ;
      RECT 34.461 31.206 34.475 31.248 ;
    END
  END r0_rd_out[49]
  PIN r0_rd_out[50]
    DIRECTION OUTPUT ;
    USE SIGNAL ;
    SHAPE ABUTMENT ;
    PORT
      LAYER M3 ;
      RECT 35.161 31.206 35.175 31.248 ;
    END
  END r0_rd_out[50]
  PIN r0_rd_out[51]
    DIRECTION OUTPUT ;
    USE SIGNAL ;
    SHAPE ABUTMENT ;
    PORT
      LAYER M3 ;
      RECT 35.861 31.206 35.875 31.248 ;
    END
  END r0_rd_out[51]
  PIN r0_rd_out[52]
    DIRECTION OUTPUT ;
    USE SIGNAL ;
    SHAPE ABUTMENT ;
    PORT
      LAYER M3 ;
      RECT 36.561 31.206 36.575 31.248 ;
    END
  END r0_rd_out[52]
  PIN r0_rd_out[53]
    DIRECTION OUTPUT ;
    USE SIGNAL ;
    SHAPE ABUTMENT ;
    PORT
      LAYER M3 ;
      RECT 37.261 31.206 37.275 31.248 ;
    END
  END r0_rd_out[53]
  PIN r0_rd_out[54]
    DIRECTION OUTPUT ;
    USE SIGNAL ;
    SHAPE ABUTMENT ;
    PORT
      LAYER M3 ;
      RECT 37.961 31.206 37.975 31.248 ;
    END
  END r0_rd_out[54]
  PIN r0_rd_out[55]
    DIRECTION OUTPUT ;
    USE SIGNAL ;
    SHAPE ABUTMENT ;
    PORT
      LAYER M3 ;
      RECT 38.661 31.206 38.675 31.248 ;
    END
  END r0_rd_out[55]
  PIN r0_rd_out[56]
    DIRECTION OUTPUT ;
    USE SIGNAL ;
    SHAPE ABUTMENT ;
    PORT
      LAYER M3 ;
      RECT 39.361 31.206 39.375 31.248 ;
    END
  END r0_rd_out[56]
  PIN r0_rd_out[57]
    DIRECTION OUTPUT ;
    USE SIGNAL ;
    SHAPE ABUTMENT ;
    PORT
      LAYER M3 ;
      RECT 40.061 31.206 40.075 31.248 ;
    END
  END r0_rd_out[57]
  PIN r0_rd_out[58]
    DIRECTION OUTPUT ;
    USE SIGNAL ;
    SHAPE ABUTMENT ;
    PORT
      LAYER M3 ;
      RECT 40.761 31.206 40.775 31.248 ;
    END
  END r0_rd_out[58]
  PIN r0_rd_out[59]
    DIRECTION OUTPUT ;
    USE SIGNAL ;
    SHAPE ABUTMENT ;
    PORT
      LAYER M3 ;
      RECT 41.461 31.206 41.475 31.248 ;
    END
  END r0_rd_out[59]
  PIN r0_rd_out[60]
    DIRECTION OUTPUT ;
    USE SIGNAL ;
    SHAPE ABUTMENT ;
    PORT
      LAYER M3 ;
      RECT 42.161 31.206 42.175 31.248 ;
    END
  END r0_rd_out[60]
  PIN r0_rd_out[61]
    DIRECTION OUTPUT ;
    USE SIGNAL ;
    SHAPE ABUTMENT ;
    PORT
      LAYER M3 ;
      RECT 42.861 31.206 42.875 31.248 ;
    END
  END r0_rd_out[61]
  PIN r0_rd_out[62]
    DIRECTION OUTPUT ;
    USE SIGNAL ;
    SHAPE ABUTMENT ;
    PORT
      LAYER M3 ;
      RECT 43.561 31.206 43.575 31.248 ;
    END
  END r0_rd_out[62]
  PIN r0_rd_out[63]
    DIRECTION OUTPUT ;
    USE SIGNAL ;
    SHAPE ABUTMENT ;
    PORT
      LAYER M3 ;
      RECT 44.261 31.206 44.275 31.248 ;
    END
  END r0_rd_out[63]
  PIN rw0_addr_in[0]
    DIRECTION INPUT ;
    USE SIGNAL ;
    SHAPE ABUTMENT ;
    PORT
      LAYER M2 ;
      RECT 0.000 22.410 0.036 22.422 ;
    END
  END rw0_addr_in[0]
  PIN rw0_addr_in[1]
    DIRECTION INPUT ;
    USE SIGNAL ;
    SHAPE ABUTMENT ;
    PORT
      LAYER M2 ;
      RECT 0.000 23.802 0.036 23.814 ;
    END
  END rw0_addr_in[1]
  PIN rw0_addr_in[2]
    DIRECTION INPUT ;
    USE SIGNAL ;
    SHAPE ABUTMENT ;
    PORT
      LAYER M2 ;
      RECT 0.000 25.194 0.036 25.206 ;
    END
  END rw0_addr_in[2]
  PIN rw0_addr_in[3]
    DIRECTION INPUT ;
    USE SIGNAL ;
    SHAPE ABUTMENT ;
    PORT
      LAYER M2 ;
      RECT 49.860 22.410 49.896 22.422 ;
    END
  END rw0_addr_in[3]
  PIN rw0_addr_in[4]
    DIRECTION INPUT ;
    USE SIGNAL ;
    SHAPE ABUTMENT ;
    PORT
      LAYER M2 ;
      RECT 49.860 23.802 49.896 23.814 ;
    END
  END rw0_addr_in[4]
  PIN rw0_addr_in[5]
    DIRECTION INPUT ;
    USE SIGNAL ;
    SHAPE ABUTMENT ;
    PORT
      LAYER M2 ;
      RECT 49.860 25.194 49.896 25.206 ;
    END
  END rw0_addr_in[5]
  PIN r0_addr_in[0]
    DIRECTION INPUT ;
    USE SIGNAL ;
    SHAPE ABUTMENT ;
    PORT
      LAYER M2 ;
      RECT 0.000 26.586 0.036 26.598 ;
    END
  END r0_addr_in[0]
  PIN r0_addr_in[1]
    DIRECTION INPUT ;
    USE SIGNAL ;
    SHAPE ABUTMENT ;
    PORT
      LAYER M2 ;
      RECT 0.000 27.978 0.036 27.990 ;
    END
  END r0_addr_in[1]
  PIN r0_addr_in[2]
    DIRECTION INPUT ;
    USE SIGNAL ;
    SHAPE ABUTMENT ;
    PORT
      LAYER M2 ;
      RECT 0.000 29.370 0.036 29.382 ;
    END
  END r0_addr_in[2]
  PIN r0_addr_in[3]
    DIRECTION INPUT ;
    USE SIGNAL ;
    SHAPE ABUTMENT ;
    PORT
      LAYER M2 ;
      RECT 49.860 26.586 49.896 26.598 ;
    END
  END r0_addr_in[3]
  PIN r0_addr_in[4]
    DIRECTION INPUT ;
    USE SIGNAL ;
    SHAPE ABUTMENT ;
    PORT
      LAYER M2 ;
      RECT 49.860 27.978 49.896 27.990 ;
    END
  END r0_addr_in[4]
  PIN r0_addr_in[5]
    DIRECTION INPUT ;
    USE SIGNAL ;
    SHAPE ABUTMENT ;
    PORT
      LAYER M2 ;
      RECT 49.860 29.370 49.896 29.382 ;
    END
  END r0_addr_in[5]
  PIN rw0_we_in
    DIRECTION INPUT ;
    USE SIGNAL ;
    SHAPE ABUTMENT ;
    PORT
      LAYER M3 ;
      RECT 44.961 31.206 44.975 31.248 ;
    END
  END rw0_we_in
  PIN rw0_ce_in
    DIRECTION INPUT ;
    USE SIGNAL ;
    SHAPE ABUTMENT ;
    PORT
      LAYER M3 ;
      RECT 45.661 31.206 45.675 31.248 ;
    END
  END rw0_ce_in
  PIN rw0_clk
    DIRECTION INPUT ;
    USE SIGNAL ;
    SHAPE ABUTMENT ;
    PORT
      LAYER M3 ;
      RECT 46.361 31.206 46.375 31.248 ;
    END
  END rw0_clk
  PIN r0_ce_in
    DIRECTION INPUT ;
    USE SIGNAL ;
    SHAPE ABUTMENT ;
    PORT
      LAYER M3 ;
      RECT 47.061 31.206 47.075 31.248 ;
    END
  END r0_ce_in
  PIN r0_clk
    DIRECTION INPUT ;
    USE SIGNAL ;
    SHAPE ABUTMENT ;
    PORT
      LAYER M3 ;
      RECT 47.761 31.206 47.775 31.248 ;
    END
  END r0_clk
  PIN VSS
    DIRECTION INOUT ;
    USE GROUND ;
    PORT
      LAYER M4 ;
      RECT 0.168 0.120 49.728 0.168 ;
      RECT 0.168 0.504 49.728 0.552 ;
      RECT 0.168 0.888 49.728 0.936 ;
      RECT 0.168 1.272 49.728 1.320 ;
      RECT 0.168 1.656 49.728 1.704 ;
      RECT 0.168 2.040 49.728 2.088 ;
      RECT 0.168 2.424 49.728 2.472 ;
      RECT 0.168 2.808 49.728 2.856 ;
      RECT 0.168 3.192 49.728 3.240 ;
      RECT 0.168 3.576 49.728 3.624 ;
      RECT 0.168 3.960 49.728 4.008 ;
      RECT 0.168 4.344 49.728 4.392 ;
      RECT 0.168 4.728 49.728 4.776 ;
      RECT 0.168 5.112 49.728 5.160 ;
      RECT 0.168 5.496 49.728 5.544 ;
      RECT 0.168 5.880 49.728 5.928 ;
      RECT 0.168 6.264 49.728 6.312 ;
      RECT 0.168 6.648 49.728 6.696 ;
      RECT 0.168 7.032 49.728 7.080 ;
      RECT 0.168 7.416 49.728 7.464 ;
      RECT 0.168 7.800 49.728 7.848 ;
      RECT 0.168 8.184 49.728 8.232 ;
      RECT 0.168 8.568 49.728 8.616 ;
      RECT 0.168 8.952 49.728 9.000 ;
      RECT 0.168 9.336 49.728 9.384 ;
      RECT 0.168 9.720 49.728 9.768 ;
      RECT 0.168 10.104 49.728 10.152 ;
      RECT 0.168 10.488 49.728 10.536 ;
      RECT 0.168 10.872 49.728 10.920 ;
      RECT 0.168 11.256 49.728 11.304 ;
      RECT 0.168 11.640 49.728 11.688 ;
      RECT 0.168 12.024 49.728 12.072 ;
      RECT 0.168 12.408 49.728 12.456 ;
      RECT 0.168 12.792 49.728 12.840 ;
      RECT 0.168 13.176 49.728 13.224 ;
      RECT 0.168 13.560 49.728 13.608 ;
      RECT 0.168 13.944 49.728 13.992 ;
      RECT 0.168 14.328 49.728 14.376 ;
      RECT 0.168 14.712 49.728 14.760 ;
      RECT 0.168 15.096 49.728 15.144 ;
      RECT 0.168 15.480 49.728 15.528 ;
      RECT 0.168 15.864 49.728 15.912 ;
      RECT 0.168 16.248 49.728 16.296 ;
      RECT 0.168 16.632 49.728 16.680 ;
      RECT 0.168 17.016 49.728 17.064 ;
      RECT 0.168 17.400 49.728 17.448 ;
      RECT 0.168 17.784 49.728 17.832 ;
      RECT 0.168 18.168 49.728 18.216 ;
      RECT 0.168 18.552 49.728 18.600 ;
      RECT 0.168 18.936 49.728 18.984 ;
      RECT 0.168 19.320 49.728 19.368 ;
      RECT 0.168 19.704 49.728 19.752 ;
      RECT 0.168 20.088 49.728 20.136 ;
      RECT 0.168 20.472 49.728 20.520 ;
      RECT 0.168 20.856 49.728 20.904 ;
      RECT 0.168 21.240 49.728 21.288 ;
      RECT 0.168 21.624 49.728 21.672 ;
      RECT 0.168 22.008 49.728 22.056 ;
      RECT 0.168 22.392 49.728 22.440 ;
      RECT 0.168 22.776 49.728 22.824 ;
      RECT 0.168 23.160 49.728 23.208 ;
      RECT 0.168 23.544 49.728 23.592 ;
      RECT 0.168 23.928 49.728 23.976 ;
      RECT 0.168 24.312 49.728 24.360 ;
      RECT 0.168 24.696 49.728 24.744 ;
      RECT 0.168 25.080 49.728 25.128 ;
      RECT 0.168 25.464 49.728 25.512 ;
      RECT 0.168 25.848 49.728 25.896 ;
      RECT 0.168 26.232 49.728 26.280 ;
      RECT 0.168 26.616 49.728 26.664 ;
      RECT 0.168 27.000 49.728 27.048 ;
      RECT 0.168 27.384 49.728 27.432 ;
      RECT 0.168 27.768 49.728 27.816 ;
      RECT 0.168 28.152 49.728 28.200 ;
      RECT 0.168 28.536 49.728 28.584 ;
      RECT 0.168 28.920 49.728 28.968 ;
      RECT 0.168 29.304 49.728 29.352 ;
      RECT 0.168 29.688 49.728 29.736 ;
      RECT 0.168 30.072 49.728 30.120 ;
      RECT 0.168 30.456 49.728 30.504 ;
      RECT 0.168 30.840 49.728 30.888 ;
    END
  END VSS
  PIN VDD
    DIRECTION INOUT ;
    USE POWER ;
    PORT
      LAYER M4 ;
      RECT 0.168 0.312 49.728 0.360 ;
      RECT 0.168 0.696 49.728 0.744 ;
      RECT 0.168 1.080 49.728 1.128 ;
      RECT 0.168 1.464 49.728 1.512 ;
      RECT 0.168 1.848 49.728 1.896 ;
      RECT 0.168 2.232 49.728 2.280 ;
      RECT 0.168 2.616 49.728 2.664 ;
      RECT 0.168 3.000 49.728 3.048 ;
      RECT 0.168 3.384 49.728 3.432 ;
      RECT 0.168 3.768 49.728 3.816 ;
      RECT 0.168 4.152 49.728 4.200 ;
      RECT 0.168 4.536 49.728 4.584 ;
      RECT 0.168 4.920 49.728 4.968 ;
      RECT 0.168 5.304 49.728 5.352 ;
      RECT 0.168 5.688 49.728 5.736 ;
      RECT 0.168 6.072 49.728 6.120 ;
      RECT 0.168 6.456 49.728 6.504 ;
      RECT 0.168 6.840 49.728 6.888 ;
      RECT 0.168 7.224 49.728 7.272 ;
      RECT 0.168 7.608 49.728 7.656 ;
      RECT 0.168 7.992 49.728 8.040 ;
      RECT 0.168 8.376 49.728 8.424 ;
      RECT 0.168 8.760 49.728 8.808 ;
      RECT 0.168 9.144 49.728 9.192 ;
      RECT 0.168 9.528 49.728 9.576 ;
      RECT 0.168 9.912 49.728 9.960 ;
      RECT 0.168 10.296 49.728 10.344 ;
      RECT 0.168 10.680 49.728 10.728 ;
      RECT 0.168 11.064 49.728 11.112 ;
      RECT 0.168 11.448 49.728 11.496 ;
      RECT 0.168 11.832 49.728 11.880 ;
      RECT 0.168 12.216 49.728 12.264 ;
      RECT 0.168 12.600 49.728 12.648 ;
      RECT 0.168 12.984 49.728 13.032 ;
      RECT 0.168 13.368 49.728 13.416 ;
      RECT 0.168 13.752 49.728 13.800 ;
      RECT 0.168 14.136 49.728 14.184 ;
      RECT 0.168 14.520 49.728 14.568 ;
      RECT 0.168 14.904 49.728 14.952 ;
      RECT 0.168 15.288 49.728 15.336 ;
      RECT 0.168 15.672 49.728 15.720 ;
      RECT 0.168 16.056 49.728 16.104 ;
      RECT 0.168 16.440 49.728 16.488 ;
      RECT 0.168 16.824 49.728 16.872 ;
      RECT 0.168 17.208 49.728 17.256 ;
      RECT 0.168 17.592 49.728 17.640 ;
      RECT 0.168 17.976 49.728 18.024 ;
      RECT 0.168 18.360 49.728 18.408 ;
      RECT 0.168 18.744 49.728 18.792 ;
      RECT 0.168 19.128 49.728 19.176 ;
      RECT 0.168 19.512 49.728 19.560 ;
      RECT 0.168 19.896 49.728 19.944 ;
      RECT 0.168 20.280 49.728 20.328 ;
      RECT 0.168 20.664 49.728 20.712 ;
      RECT 0.168 21.048 49.728 21.096 ;
      RECT 0.168 21.432 49.728 21.480 ;
      RECT 0.168 21.816 49.728 21.864 ;
      RECT 0.168 22.200 49.728 22.248 ;
      RECT 0.168 22.584 49.728 22.632 ;
      RECT 0.168 22.968 49.728 23.016 ;
      RECT 0.168 23.352 49.728 23.400 ;
      RECT 0.168 23.736 49.728 23.784 ;
      RECT 0.168 24.120 49.728 24.168 ;
      RECT 0.168 24.504 49.728 24.552 ;
      RECT 0.168 24.888 49.728 24.936 ;
      RECT 0.168 25.272 49.728 25.320 ;
      RECT 0.168 25.656 49.728 25.704 ;
      RECT 0.168 26.040 49.728 26.088 ;
      RECT 0.168 26.424 49.728 26.472 ;
      RECT 0.168 26.808 49.728 26.856 ;
      RECT 0.168 27.192 49.728 27.240 ;
      RECT 0.168 27.576 49.728 27.624 ;
      RECT 0.168 27.960 49.728 28.008 ;
      RECT 0.168 28.344 49.728 28.392 ;
      RECT 0.168 28.728 49.728 28.776 ;
      RECT 0.168 29.112 49.728 29.160 ;
      RECT 0.168 29.496 49.728 29.544 ;
      RECT 0.168 29.880 49.728 29.928 ;
      RECT 0.168 30.264 49.728 30.312 ;
      RECT 0.168 30.648 49.728 30.696 ;
      RECT 0.168 31.032 49.728 31.080 ;
    END
  END VDD
  OBS
    LAYER M1 ;
    RECT 0 0 49.896 31.248 ;
    LAYER M2 ;
    RECT 0 0 49.896 31.248 ;
    LAYER M3 ;
    RECT 0 0 49.896 31.248 ;
    LAYER M4 ;
    RECT 0 0 49.896 31.248 ;
  END
END fakeram_1rw1r_64w64d_sram

END LIBRARY
